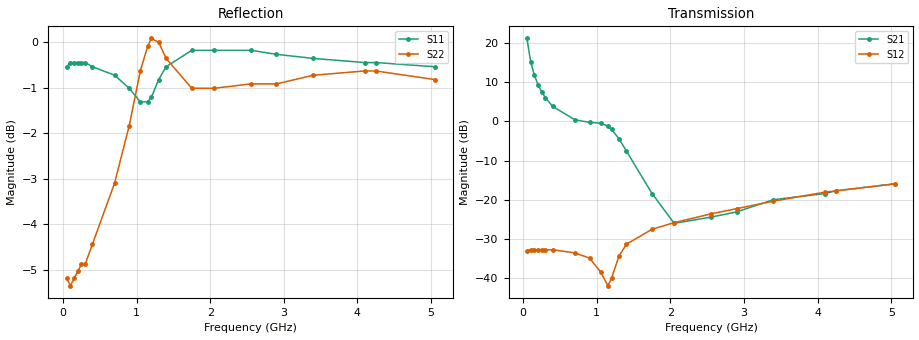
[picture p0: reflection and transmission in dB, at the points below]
!AT-36408
!S-PARAMETERS at Vce=3.6 V  Ic=50 mA.  LAST UPDATED 08-05-96
# ghz s ma r 50
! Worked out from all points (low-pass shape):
!   101 points, 50 MHz to 5.05 GHz, reference 50 ohm
!   highest |S21| = 21.19 dB at 50 MHz (marker M1); lowest = -26.0 dB at 2.05 GHz (marker M2)
!   |S21| within 3 dB of the highest: start of sweep to 75.39 MHz
!   lowest |S11| = -1.3 dB at 1.05 GHz (marker M3), VSWR 13.29, Z = 3.79 + j4.35 ohm
!   |S11| at or under -10 dB: nowhere
!   |S22| runs from -5.4 to 0.1 dB; largest |S21 - S12| = 11
!   S11 on the Smith chart (normalised r, x): 50 MHz: 0.03, -0.09; 700 MHz: 0.04, +0.07; 2.9 GHz: 0.02, +0.28; 4.1 GHz: 0.03, +0.46; 5.05 GHz: 0.04, +0.66
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0.05  0.94 -170.0  11.47 94.0  0.022 9.0  0.55 -157.0
0.1  0.95 -176.0  5.81 86.0  0.023 5.0  0.54 -166.0
0.15  0.95 -178.0  3.9 82.0  0.023 4.0  0.55 -168.0
0.2  0.95 -180.0  2.95 77.0  0.023 4.0  0.56 -167.0
0.25  0.95 179.0  2.38 73.0  0.023 3.0  0.57 -167.0
0.3  0.95 178.0  2.01 69.0  0.023 3.0  0.57 -166.0
0.4  0.94 176.0  1.55 61.0  0.023 3.0  0.6 -164.0
0.7  0.92 172.0  1.05 36.0  0.021 -1.0  0.7 -158.0
0.9  0.89 170.0  0.97 12.0  0.018 -15.0  0.81 -157.0
1.05  0.86 170.0  0.95 -14.0  0.012 -50.0  0.93 -159.0
1.15  0.86 172.0  0.87 -38.0  0.008 -126.0  0.99 -164.0
1.2  0.87 173.0  0.79 -51.0  0.01 -171.0  1.01 -166.0
1.3  0.91 173.0  0.6 -75.0  0.019 144.0  1 -171.0
1.4  0.94 171.0  0.42 -94.0  0.027 122.0  0.96 -174.0
1.75  0.98 165.0  0.12 -142.0  0.042 93.0  0.89 -175.0
2.05  0.98 161.0  0.05 166.0  0.051 85.0  0.89 -175.0
2.55  0.98 154.0  0.06 99.0  0.066 79.0  0.9 -176.0
2.9  0.97 149.0  0.07 84.0  0.077 75.0  0.9 -177.0
3.4  0.96 142.0  0.1 73.0  0.096 71.0  0.92 -178.0
4.1  0.95 131.0  0.12 62.0  0.125 61.0  0.93 177.0
4.25  0.95 129.0  0.13 60.0  0.13 59.0  0.93 176.0
5.05  0.94 113.0  0.16 48.0  0.159 49.0  0.91 169.0
